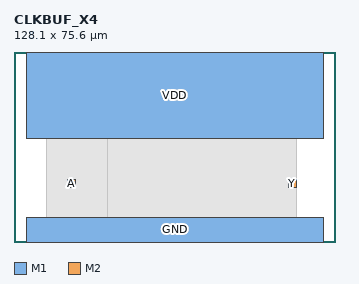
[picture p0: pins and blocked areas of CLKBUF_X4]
MACRO CLKBUF_X4
  CLASS CORE ;
  ORIGIN 0 0 ;
  SIZE 128.100 BY 75.600 ;
  SYMMETRY X Y ;
  SITE TR1um_access_site ;
  PIN VDD
    DIRECTION INOUT ;
    USE POWER ;
    PORT
      LAYER M1 ;
        RECT 5.000 41.000 123.100 75.600 ;
    END
  END VDD
  PIN GND
    DIRECTION INOUT ;
    USE GROUND ;
    PORT
      LAYER M1 ;
        RECT 5.000 0.000 123.100 9.800 ;
    END
  END GND
  PIN A
    DIRECTION INPUT ;
    USE SIGNAL ;
    PORT
      LAYER M2 ;
        RECT 21.100 21.600 24.500 25.000 ;
    END
  END A
  PIN Y
    DIRECTION OUTPUT ;
    USE SIGNAL ;
    PORT
      LAYER M2 ;
        RECT 109.100 21.600 112.500 25.000 ;
    END
  END Y
  OBS
    LAYER M1 ;
      RECT 15.100 16.400 29.700 34.400 ;
    LAYER M1 ;
      RECT 13.100 6.400 105.700 51.200 ;
    LAYER M1 ;
      RECT 37.100 6.400 112.500 51.200 ;
    LAYER V1 ;
      RECT 22.100 22.600 23.500 24.000 ;
    LAYER V1 ;
      RECT 110.100 22.600 111.500 24.000 ;
  END
END CLKBUF_X4
